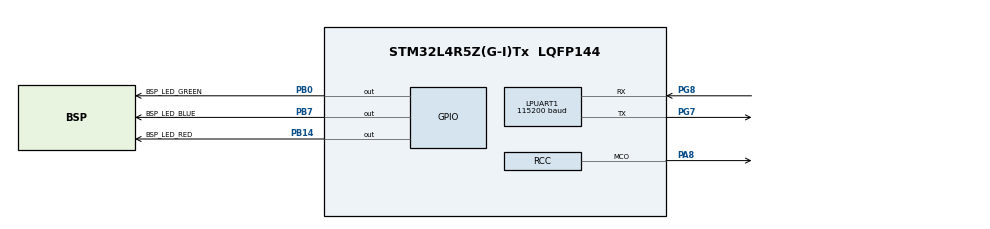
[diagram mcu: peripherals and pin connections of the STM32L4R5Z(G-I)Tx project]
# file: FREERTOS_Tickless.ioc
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FREERTOS.Tasks01=defaultTask,24,128,StartDefaultTask,Default,NULL,Dynamic,NULL,NULL
FREERTOS.configTOTAL_HEAP_SIZE=30000
FREERTOS.configUSE_NEWLIB_REENTRANT=1
FREERTOS.configUSE_TICKLESS_IDLE=1
LPTIM1.ClockPrescaler=LPTIM_PRESCALER_DIV32
LPUART1.BaudRate=115200
LPUART1.WordLength=UART_WORDLENGTH_8B
Mcu.Family=STM32L4
Mcu.Name=STM32L4R5Z(G-I)Tx
Mcu.Package=LQFP144
NVIC.LPTIM1_IRQn=true\:5\:0\:false\:false\:true\:true\:true\:true\:true
NVIC.LPUART1_IRQn=true\:5\:0\:false\:false\:true\:true\:true\:true\:true
NVIC.PriorityGroup=NVIC_PRIORITYGROUP_4
NVIC.TIM6_DAC_IRQn=true\:15\:0\:false\:false\:true\:false\:false\:true\:true
NVIC.TimeBase=TIM6_DAC_IRQn
NVIC.TimeBaseIP=TIM6
PA13\ (JTMS/SWDIO).Mode=JTAG_4_pins
PA13\ (JTMS/SWDIO).Signal=SYS_JTMS-SWDIO
PA14\ (JTCK/SWCLK).Mode=JTAG_4_pins
PA14\ (JTCK/SWCLK).Signal=SYS_JTCK-SWCLK
PA15\ (JTDI).Mode=JTAG_4_pins
PA15\ (JTDI).Signal=SYS_JTDI
PA8.Mode=Clock-out
PA8.Signal=RCC_MCO
PB0.GPIO_Label=BSP_LED_GREEN
PB0.Signal=GPIO_Output
PB14.GPIO_Label=BSP_LED_RED
PB14.Signal=GPIO_Output
PB3\ (JTDO/TRACESWO).Mode=JTAG_4_pins
PB3\ (JTDO/TRACESWO).Signal=SYS_JTDO-SWO
PB7.GPIO_Label=BSP_LED_BLUE
PB7.Signal=GPIO_Output
PC14-OSC32_IN\ (PC14).Mode=LSE-External-Oscillator
PC14-OSC32_IN\ (PC14).Signal=RCC_OSC32_IN
PC15-OSC32_OUT\ (PC15).Mode=LSE-External-Oscillator
PC15-OSC32_OUT\ (PC15).Signal=RCC_OSC32_OUT
PG7.Mode=Asynchronous
PG7.Signal=LPUART1_TX
PG8.Mode=Asynchronous
PG8.Signal=LPUART1_RX
ProjectManager.HeapSize=0x200
ProjectManager.StackSize=0x400
ProjectManager.TargetToolchain=CMake
RCC.HSE_VALUE=8000000
RCC.HSI48_VALUE=48000000
RCC.HSI_VALUE=16000000
RCC.LPTIM1CLockSelection=RCC_LPTIM1CLKSOURCE_LSE
RCC.LPUART1CLockSelection=RCC_LPUART1CLKSOURCE_HSI
RCC.MSI_VALUE=4000000
RCC.VCOOutputFreq_Value=32000000
VP_FREERTOS_VS_CMSIS_V2.Mode=CMSIS_V2
VP_LPTIM1_VS_LPTIM_counterModeInternalClock.Mode=Counts__internal_clock_event_00
VP_SYS_VS_LPOM.Mode=PowerOptimisation
VP_SYS_VS_tim6.Mode=TIM6
board=custom

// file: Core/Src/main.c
/* USER CODE BEGIN Header */
/**
  ******************************************************************************
  * @file           : main.c
  * @brief          : Main program body
  ******************************************************************************
  * @attention
  *
  * Copyright (c) 2026 STMicroelectronics.
  * All rights reserved.
  *
  * This software is licensed under terms that can be found in the LICENSE file
  * in the root directory of this software component.
  * If no LICENSE file comes with this software, it is provided AS-IS.
  *
  ******************************************************************************
  */
#include "main.h"
#include "cmsis_os.h"
#include "lptim.h"
#include "usart.h"
#include "gpio.h"

#include "App.h"

void MX_FREERTOS_Init(void);

int main(void)
{
  /* Reset of all peripherals, Initializes the Flash interface and the Systick. */
  HAL_Init();
  /* Configure the system clock */
  SystemClock_Config();

    /* Enable Power Clock */
  __HAL_RCC_PWR_CLK_ENABLE();

  /* Ensure that MSI is wake-up system clock */
  __HAL_RCC_WAKEUPSTOP_CLK_CONFIG(RCC_STOP_WAKEUPCLOCK_MSI);

  /* Enable the debugging while in ULP mode. */
  HAL_EnableDBGSleepMode();

  /* Initialize all configured peripherals */
  MX_GPIO_Init();
  MX_LPTIM1_Init();
  MX_LPUART1_UART_Init();

  App_Init();

  /* Init scheduler */
  vTaskStartScheduler();

  /* If all is well, the scheduler will now be running, and the following line
  will never be reached.  If the following line does execute, then there was
  insufficient FreeRTOS heap memory available for the idle and/or timer tasks
  to be created.  See the memory management section on the FreeRTOS web site
  for more details.  */
  for (;;);
}

void SystemClock_Config(void)
{
  RCC_OscInitTypeDef RCC_OscInitStruct = {0};
  RCC_ClkInitTypeDef RCC_ClkInitStruct = {0};

  /** Configure the main internal regulator output voltage
  */
  if (HAL_PWREx_ControlVoltageScaling(PWR_REGULATOR_VOLTAGE_SCALE1_BOOST) != HAL_OK)
  {
    Error_Handler();
  }

  /** Configure LSE Drive Capability
  */
  HAL_PWR_EnableBkUpAccess();
  __HAL_RCC_LSEDRIVE_CONFIG(RCC_LSEDRIVE_LOW);

  /** Initializes the RCC Oscillators according to the specified parameters
  * in the RCC_OscInitTypeDef structure.
  */
  RCC_OscInitStruct.OscillatorType = RCC_OSCILLATORTYPE_HSI|RCC_OSCILLATORTYPE_LSE
                              |RCC_OSCILLATORTYPE_MSI;
  RCC_OscInitStruct.LSEState = RCC_LSE_ON;
  RCC_OscInitStruct.HSIState = RCC_HSI_ON;
  RCC_OscInitStruct.HSICalibrationValue = RCC_HSICALIBRATION_DEFAULT;
  RCC_OscInitStruct.MSIState = RCC_MSI_ON;
  RCC_OscInitStruct.MSICalibrationValue = 0;
  RCC_OscInitStruct.MSIClockRange = RCC_MSIRANGE_6;
  RCC_OscInitStruct.PLL.PLLState = RCC_PLL_ON;
  RCC_OscInitStruct.PLL.PLLSource = RCC_PLLSOURCE_MSI;
  RCC_OscInitStruct.PLL.PLLM = 1;
  RCC_OscInitStruct.PLL.PLLN = 60;
  RCC_OscInitStruct.PLL.PLLP = RCC_PLLP_DIV2;
  RCC_OscInitStruct.PLL.PLLQ = RCC_PLLQ_DIV2;
  RCC_OscInitStruct.PLL.PLLR = RCC_PLLR_DIV2;
  if (HAL_RCC_OscConfig(&RCC_OscInitStruct) != HAL_OK)
  {
    Error_Handler();
  }

  /** Initializes the CPU, AHB and APB buses clocks
  */
  RCC_ClkInitStruct.ClockType = RCC_CLOCKTYPE_HCLK|RCC_CLOCKTYPE_SYSCLK
                              |RCC_CLOCKTYPE_PCLK1|RCC_CLOCKTYPE_PCLK2;
  RCC_ClkInitStruct.SYSCLKSource = RCC_SYSCLKSOURCE_PLLCLK;
  RCC_ClkInitStruct.AHBCLKDivider = RCC_SYSCLK_DIV1;
  RCC_ClkInitStruct.APB1CLKDivider = RCC_HCLK_DIV1;
  RCC_ClkInitStruct.APB2CLKDivider = RCC_HCLK_DIV1;

  if (HAL_RCC_ClockConfig(&RCC_ClkInitStruct, FLASH_LATENCY_5) != HAL_OK)
  {
    Error_Handler();
  }
}

void HAL_TIM_PeriodElapsedCallback(TIM_HandleTypeDef *htim)
{
  if (htim->Instance == TIM6)
  {
    HAL_IncTick();
  }
}

void Error_Handler(void)
{
  __disable_irq();
  while (1)
  {
  }
}

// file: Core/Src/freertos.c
/* USER CODE BEGIN Header */
/**
  ******************************************************************************
  * File Name          : freertos.c
  * Description        : Code for freertos applications
  ******************************************************************************
  * @attention
  *
  * Copyright (c) 2026 STMicroelectronics.
  * All rights reserved.
  *
  * This software is licensed under terms that can be found in the LICENSE file
  * in the root directory of this software component.
  * If no LICENSE file comes with this software, it is provided AS-IS.
  *
  ******************************************************************************
  */
/* USER CODE END Header */

#include "FreeRTOS.h"
#include "task.h"
#include "main.h"
#include "cmsis_os.h"

/* Definitions for defaultTask */
osThreadId_t defaultTaskHandle;
const osThreadAttr_t defaultTask_attributes = {
  .name = "defaultTask",
  .stack_size = 128 * 4,
  .priority = (osPriority_t) osPriorityNormal,
};

void StartDefaultTask(void *argument);

void MX_FREERTOS_Init(void); /* (MISRA C 2004 rule 8.1) */

void MX_FREERTOS_Init(void) {

  /* Create the thread(s) */
  /* creation of defaultTask */
  defaultTaskHandle = osThreadNew(StartDefaultTask, NULL, &defaultTask_attributes);

}

void StartDefaultTask(void *argument)
{
  for(;;)
  {
    osDelay(1);
  }
}
